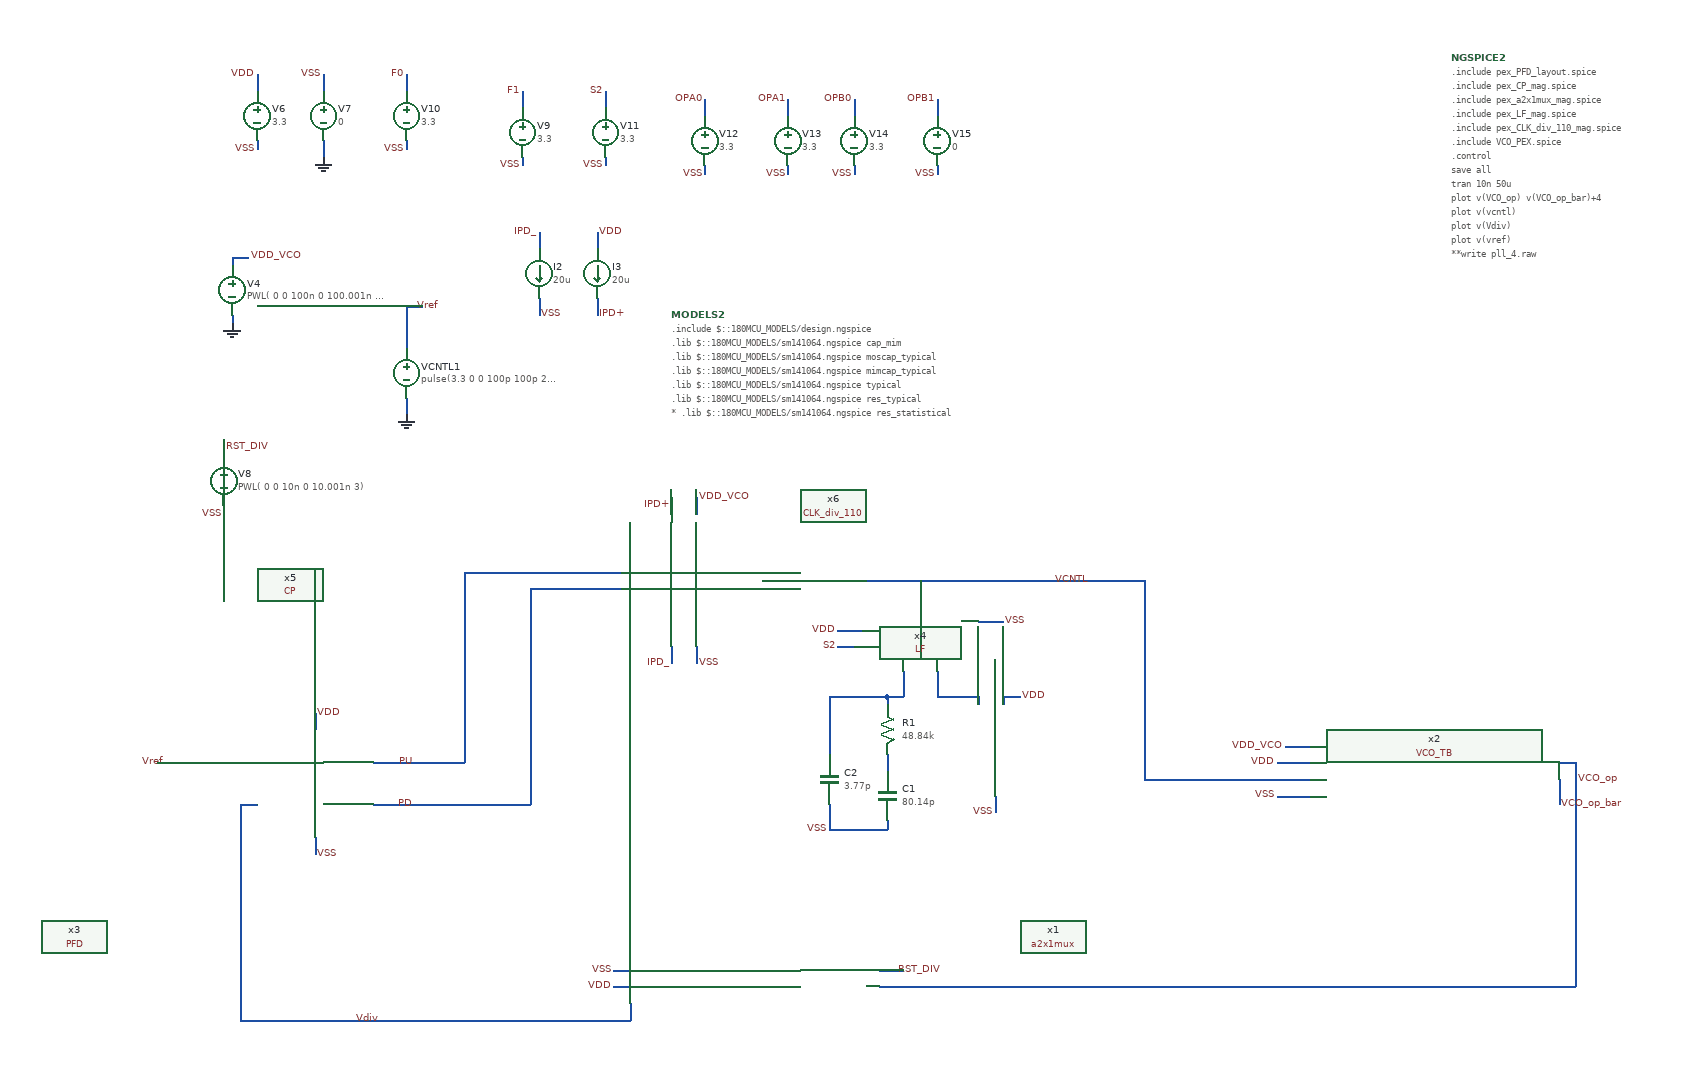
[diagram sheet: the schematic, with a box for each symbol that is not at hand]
v {xschem version=3.1.0 file_version=1.2
}
G {}
K {}
V {}
S {}
E {}
N 570 -560 570 -540 {
lab=VDD}
N 570 -410 570 -390 {
lab=VSS}
N 480 -500 500 -500 {
lab=Vref}
N 480 -450 500 -450 {
lab=Vdiv}
N 640 -450 660 -450 {
lab=PD}
N 400 -500 460 -500 {
lab=Vref}
N 460 -500 480 -500 {
lab=Vref}
N 660 -500 750 -500 {
lab=PU}
N 660 -450 750 -450 {
lab=PD}
N 480 -450 480 -320 {
lab=Vdiv}
N 480 -220 480 -190 {
lab=Vdiv}
N 490 -190 780 -190 {
lab=Vdiv}
N 480 -320 480 -220 {
lab=Vdiv}
N 480 -190 490 -190 {
lab=Vdiv}
N 640 -500 660 -500 {
lab=PU}
N 680 -940 680 -920 {
lab=GND}
N 470 -1040 470 -1030 {
lab=GND}
N 680 -1050 700 -1050 {
lab=Vref}
N 500 -1250 500 -1240 {
lab=VSS}
N 500 -1330 500 -1310 {
lab=VDD}
N 580 -1330 580 -1310 {
lab=VSS}
N 580 -1250 580 -1230 {
lab=GND}
N 780 -190 950 -190 {
lab=Vdiv}
N 1280 -230 1930 -230 {
lab=VCO_op}
N 460 -810 460 -800 {
lab=VSS}
N 460 -890 460 -870 {
lab=RST_DIV}
N 2090 -480 2090 -460 {
lab=VCO_op}
N 680 -1050 680 -1000 {
lab=Vref}
N 1250 -230 1270 -230 {
lab=VCO_op}
N 1270 -230 1280 -230 {
lab=VCO_op}
N 470 -1110 470 -1100 {
lab=VDD_VCO}
N 470 -1110 490 -1110 {
lab=VDD_VCO}
N 820 -1230 820 -1220 {
lab=VSS}
N 820 -1310 820 -1290 {
lab=F1}
N 680 -1250 680 -1240 {
lab=VSS}
N 680 -1330 680 -1310 {
lab=F0}
N 920 -1230 920 -1220 {
lab=VSS}
N 920 -1310 920 -1290 {
lab=S2}
N 1040 -1220 1040 -1210 {
lab=VSS}
N 1040 -1300 1040 -1280 {
lab=OPA0}
N 1140 -1220 1140 -1210 {
lab=VSS}
N 1140 -1300 1140 -1280 {
lab=OPA1}
N 1220 -1220 1220 -1210 {
lab=VSS}
N 1220 -1300 1220 -1280 {
lab=OPB0}
N 1320 -1220 1320 -1210 {
lab=VSS}
N 1320 -1300 1320 -1280 {
lab=OPB1}
N 1030 -820 1030 -800 {
lab=VDD_VCO}
N 1030 -640 1030 -620 {
lab=VSS}
N 920 -730 940 -730 {
lab=PU}
N 920 -710 940 -710 {
lab=PD}
N 1000 -820 1000 -800 {
lab=IPD+}
N 1000 -640 1000 -620 {
lab=IPD_}
N 840 -1060 840 -1040 {
lab=VSS}
N 910 -1060 910 -1040 {
lab=IPD+}
N 840 -1140 840 -1120 {
lab=IPD_}
N 910 -1140 910 -1120 {
lab=VDD}
N 380 -500 410 -500 {
lab=Vref}
N 1570 -480 1610 -480 {
lab=VCNTL}
N 2090 -500 2090 -480 {
lab=VCO_op}
N 2070 -500 2090 -500 {
lab=VCO_op}
N 2070 -480 2070 -450 {
lab=VCO_op_bar}
N 950 -210 950 -190 {
lab=Vdiv}
N 940 -230 950 -230 {
lab=VDD}
N 930 -230 940 -230 {
lab=VDD}
N 930 -250 950 -250 {
lab=VSS}
N 1250 -250 1280 -250 {
lab=RST_DIV}
N 1740 -520 1770 -520 {
lab=VDD_VCO}
N 1610 -480 1770 -480 {
lab=VCNTL}
N 1390 -460 1390 -440 {
lab=VSS}
N 1400 -580 1400 -570 {
lab=VDD}
N 1400 -580 1420 -580 {
lab=VDD}
N 1200 -640 1220 -640 {
lab=S2}
N 1200 -660 1220 -660 {
lab=VDD}
N 1370 -670 1400 -670 {
lab=VSS}
N 1190 -450 1190 -420 {
lab=VSS}
N 1190 -420 1260 -420 {
lab=VSS}
N 1190 -580 1190 -510 {
lab=#net1}
N 1190 -580 1260 -580 {
lab=#net1}
N 1260 -580 1260 -570 {
lab=#net1}
N 1220 -660 1230 -660 {
lab=VDD}
N 1180 -720 1360 -720 {
lab=VCNTL}
N 1260 -510 1260 -490 {
lab=#net2}
N 1260 -430 1260 -420 {
lab=VSS}
N 1260 -580 1280 -580 {
lab=#net1}
N 1280 -610 1280 -580 {
lab=#net1}
N 1370 -580 1370 -570 {
lab=#net3}
N 1320 -580 1370 -580 {
lab=#net3}
N 1320 -610 1320 -580 {
lab=#net3}
N 1300 -720 1300 -710 {
lab=VCNTL}
N 1570 -710 1570 -480 {
lab=VCNTL}
N 1570 -720 1570 -710 {
lab=VCNTL}
N 1360 -720 1570 -720 {
lab=VCNTL}
N 1110 -720 1180 -720 {
lab=VCNTL}
N 750 -730 920 -730 {
lab=PU}
N 750 -730 750 -500 {
lab=PU}
N 750 -450 830 -450 {
lab=PD}
N 830 -710 830 -450 {
lab=PD}
N 830 -710 920 -710 {
lab=PD}
N 1730 -460 1770 -460 {
lab=VSS}
N 1730 -500 1770 -500 {
lab=VDD}
N 2090 -460 2090 -230 {
lab=VCO_op}
N 1930 -230 2090 -230 {
lab=VCO_op}
C {devices/lab_pin.sym} 570 -560 2 0 {name=p22 sig_type=std_logic lab=VDD}
C {devices/lab_wire.sym} 570 -390 2 0 {name=p23 sig_type=std_logic lab=VSS}
C {devices/lab_pin.sym} 650 -190 3 0 {name=p25 sig_type=std_logic lab=Vdiv
}
C {devices/lab_pin.sym} 2090 -480 2 0 {name=p26 sig_type=std_logic lab=VCO_op
}
C {devices/vsource.sym} 680 -970 0 0 {name=VCNTL1 value="pulse(3.3 0 0 100p 100p 250n 500n)"}
C {devices/gnd.sym} 680 -920 0 0 {name=l4 lab=GND}
C {devices/gnd.sym} 470 -1030 0 0 {name=l5 lab=GND}
C {devices/vsource.sym} 470 -1070 0 0 {name=V4 value=" PWL( 0 0 100n 0 100.001n 3.3)"}
C {devices/code_shown.sym} 1940 -1350 0 1 {name=NGSPICE2 only_toplevel=true
value="
.include "pex_PFD_layout.spice"
.include "pex_CP_mag.spice"
.include "pex_a2x1mux_mag.spice"
.include "pex_LF_mag.spice"
.include "pex_CLK_div_110_mag.spice"
.include "VCO_PEX.spice"
.control
save all
tran 10n 50u 
plot v(VCO_op) v(VCO_op_bar)+4
plot v(vcntl)
plot v(Vdiv)
plot v(vref)
**write pll_4.raw
.endc
"}
C {devices/vsource.sym} 500 -1280 0 0 {name=V6 value=3.3}
C {devices/vsource.sym} 580 -1280 0 0 {name=V7 value=0}
C {devices/lab_wire.sym} 580 -1330 0 0 {name=p27 sig_type=std_logic lab=VSS}
C {devices/lab_wire.sym} 500 -1240 0 0 {name=p29 sig_type=std_logic lab=VSS
}
C {devices/lab_wire.sym} 500 -1330 0 0 {name=p30 sig_type=std_logic lab=VDD}
C {devices/gnd.sym} 580 -1230 0 0 {name=l6 lab=GND}
C {devices/lab_pin.sym} 2070 -450 2 0 {name=p31 sig_type=std_logic lab=VCO_op_bar
}
C {devices/lab_pin.sym} 490 -1110 2 0 {name=p32 sig_type=std_logic lab=VDD_VCO}
C {devices/lab_pin.sym} 690 -1050 2 0 {name=p33 sig_type=std_logic lab=Vref
}
C {devices/lab_wire.sym} 460 -800 0 0 {name=p34 sig_type=std_logic lab=VSS
}
C {devices/vsource.sym} 460 -840 0 0 {name=V8 value=" PWL( 0 0 10n 0 10.001n 3)"}
C {devices/lab_pin.sym} 690 -500 1 0 {name=p37 sig_type=std_logic lab=PU}
C {devices/lab_pin.sym} 690 -450 1 0 {name=p40 sig_type=std_logic lab=PD}
C {devices/vsource.sym} 820 -1260 0 0 {name=V9 value=3.3}
C {devices/lab_wire.sym} 820 -1220 0 0 {name=p41 sig_type=std_logic lab=VSS
}
C {devices/lab_wire.sym} 820 -1310 0 0 {name=p42 sig_type=std_logic lab=F1}
C {devices/vsource.sym} 680 -1280 0 0 {name=V10 value=3.3}
C {devices/lab_wire.sym} 680 -1240 0 0 {name=p43 sig_type=std_logic lab=VSS
}
C {devices/lab_wire.sym} 680 -1330 0 0 {name=p44 sig_type=std_logic lab=F0}
C {devices/vsource.sym} 920 -1260 0 0 {name=V11 value=3.3}
C {devices/lab_wire.sym} 920 -1220 0 0 {name=p45 sig_type=std_logic lab=VSS
}
C {devices/lab_wire.sym} 920 -1310 0 0 {name=p46 sig_type=std_logic lab=S2}
C {devices/vsource.sym} 1040 -1250 0 0 {name=V12 value=3.3}
C {devices/lab_wire.sym} 1040 -1210 0 0 {name=p59 sig_type=std_logic lab=VSS
}
C {devices/lab_wire.sym} 1040 -1300 0 0 {name=p60 sig_type=std_logic lab=OPA0}
C {devices/vsource.sym} 1140 -1250 0 0 {name=V13 value=3.3}
C {devices/lab_wire.sym} 1140 -1210 0 0 {name=p61 sig_type=std_logic lab=VSS
}
C {devices/lab_wire.sym} 1140 -1300 0 0 {name=p62 sig_type=std_logic lab=OPA1}
C {devices/vsource.sym} 1220 -1250 0 0 {name=V14 value=3.3}
C {devices/lab_wire.sym} 1220 -1210 0 0 {name=p63 sig_type=std_logic lab=VSS
}
C {devices/lab_wire.sym} 1220 -1300 0 0 {name=p64 sig_type=std_logic lab=OPB0
}
C {devices/vsource.sym} 1320 -1250 0 0 {name=V15 value=0}
C {devices/lab_wire.sym} 1320 -1210 0 0 {name=p65 sig_type=std_logic lab=VSS
}
C {devices/lab_wire.sym} 1320 -1300 0 0 {name=p66 sig_type=std_logic lab=OPB1}
C {devices/lab_pin.sym} 460 -880 2 0 {name=p67 sig_type=std_logic lab=RST_DIV}
C {devices/lab_wire.sym} 1030 -620 2 0 {name=p68 sig_type=std_logic lab=VSS}
C {devices/lab_wire.sym} 1000 -810 0 0 {name=p70 sig_type=std_logic lab=IPD+}
C {devices/lab_wire.sym} 1000 -620 0 0 {name=p71 sig_type=std_logic lab=IPD_}
C {devices/isource.sym} 840 -1090 0 0 {name=I2 value=20u}
C {devices/isource.sym} 910 -1090 0 0 {name=I3 value=20u}
C {devices/lab_wire.sym} 840 -1140 0 0 {name=p72 sig_type=std_logic lab=IPD_}
C {devices/lab_wire.sym} 910 -1040 2 0 {name=p73 sig_type=std_logic lab=IPD+}
C {devices/lab_wire.sym} 840 -1040 2 0 {name=p74 sig_type=std_logic lab=VSS}
C {devices/lab_wire.sym} 910 -1140 2 0 {name=p75 sig_type=std_logic lab=VDD}
C {devices/lab_pin.sym} 390 -500 0 0 {name=p76 sig_type=std_logic lab=Vref
}
C {devices/code_shown.sym} 1000 -1040 0 0 {name=MODELS2 only_toplevel=true
format="tcleval( @value )"
value="
.include $::180MCU_MODELS/design.ngspice
.lib $::180MCU_MODELS/sm141064.ngspice cap_mim
.lib $::180MCU_MODELS/sm141064.ngspice moscap_typical
.lib $::180MCU_MODELS/sm141064.ngspice mimcap_typical
.lib $::180MCU_MODELS/sm141064.ngspice typical
.lib $::180MCU_MODELS/sm141064.ngspice res_typical
* .lib $::180MCU_MODELS/sm141064.ngspice res_statistical
"}
C {devices/lab_wire.sym} 930 -250 0 0 {name=p78 sig_type=std_logic lab=VSS}
C {devices/lab_pin.sym} 930 -230 0 0 {name=p79 sig_type=std_logic lab=VDD}
C {devices/lab_pin.sym} 1270 -250 2 0 {name=p80 sig_type=std_logic lab=RST_DIV}
C {devices/lab_pin.sym} 1030 -820 2 0 {name=p81 sig_type=std_logic lab=VDD_VCO}
C {devices/lab_pin.sym} 1740 -520 0 0 {name=p89 sig_type=std_logic lab=VDD_VCO}
C {devices/lab_wire.sym} 1390 -440 2 1 {name=p5 sig_type=std_logic lab=VSS}
C {devices/lab_wire.sym} 1460 -720 2 0 {name=p20 sig_type=std_logic lab=VCNTL}
C {devices/lab_wire.sym} 1420 -580 0 1 {name=p21 sig_type=std_logic lab=VDD}
C {devices/lab_wire.sym} 1400 -670 2 0 {name=p6 sig_type=std_logic lab=VSS}
C {devices/lab_wire.sym} 1200 -660 2 1 {name=p1 sig_type=std_logic lab=VDD}
C {devices/lab_wire.sym} 1200 -640 1 1 {name=p2 sig_type=std_logic lab=S2}
C {devices/capa.sym} 1260 -460 0 0 {name=C1
m=1
value=80.14p
footprint=1206
device="ceramic capacitor"}
C {devices/capa.sym} 1190 -480 0 0 {name=C2
m=1
value=3.77p
footprint=1206
device="ceramic capacitor"}
C {devices/res.sym} 1260 -540 0 0 {name=R1
value=48.84k
footprint=1206
device=resistor
m=1}
C {devices/lab_wire.sym} 1190 -420 2 1 {name=p3 sig_type=std_logic lab=VSS}
C {devices/lab_wire.sym} 1730 -460 2 1 {name=p4 sig_type=std_logic lab=VSS}
C {devices/lab_pin.sym} 1730 -500 0 0 {name=p7 sig_type=std_logic lab=VDD}
C {PFD.sym} 280 -290 0 0 {name=x3}
C {CP.sym} 450 -520 0 0 {name=x5}
C {a2x1mux.sym} 1460 -290 3 0 {name=x1}
C {LF.sym} 1530 -410 0 1 {name=x4}
C {VCO_TB.sym} 1920 -490 0 0 {name=x2}
C {CLK_div_110.sym} 1100 -230 0 1 {name=x6}
